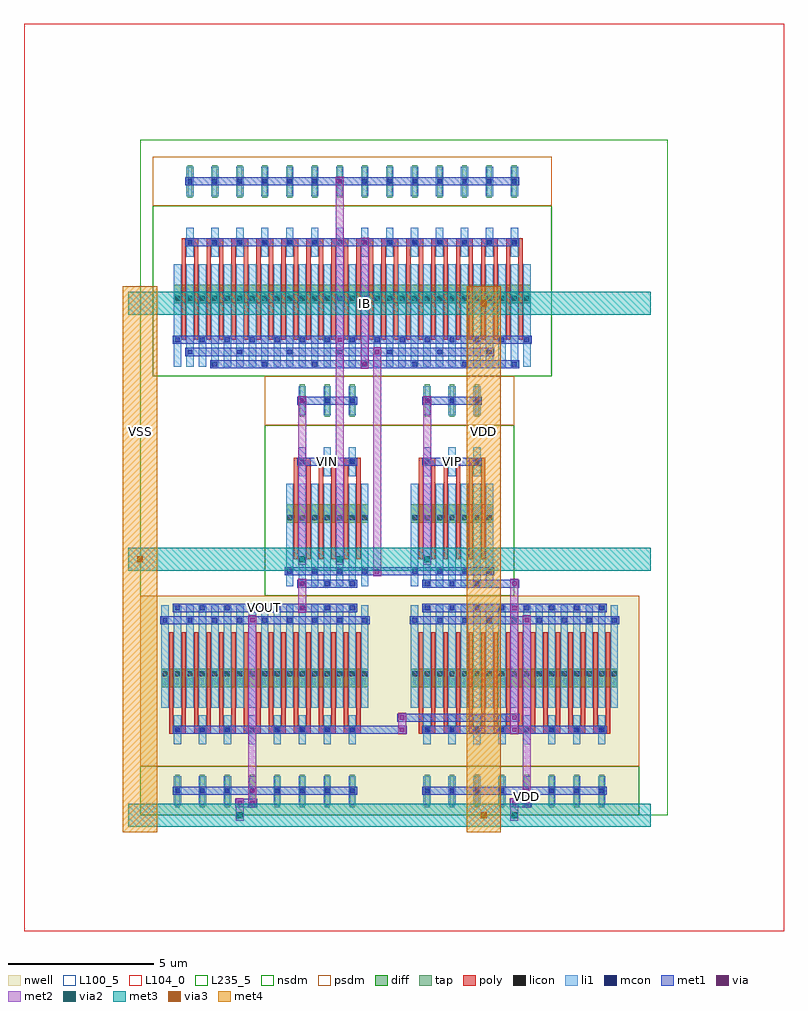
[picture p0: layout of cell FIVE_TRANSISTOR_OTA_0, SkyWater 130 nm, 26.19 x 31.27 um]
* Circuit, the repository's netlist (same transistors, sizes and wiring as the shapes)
* NGSPICE file created from FIVE_TRANSISTOR_OTA_0.ext - technology: sky130A

.subckt DCL_PMOS_S_33011438_X8_Y1_1774868971 a_200_252# w_0_0#
X0 a_200_252# a_200_252# w_0_0# w_0_0# sky130_fd_pr__pfet_01v8 ad=0.0882 pd=0.91 as=0.0882 ps=0.91 w=0.63 l=0.15 M=16
.ends

.subckt NMOS_4T_45526871_X3_Y1_1774868972 a_147_504# a_200_252# a_230_504# a_241_1232#
X0 a_230_504# a_200_252# a_147_504# a_241_1232# sky130_fd_pr__nfet_01v8 ad=0.0882 pd=0.91 as=0.16695 ps=1.79 w=0.63 l=0.15 M=6
.ends

.subckt SCM_NMOS_53863688_X7_Y1_1774868974 a_147_504# a_200_252# a_402_504#
X0 a_147_504# a_200_252# a_200_252# a_147_504# sky130_fd_pr__nfet_01v8 ad=0.0882 pd=0.91 as=0.0882 ps=0.91 w=0.63 l=0.15 M=14
X1 a_402_504# a_200_252# a_147_504# a_147_504# sky130_fd_pr__nfet_01v8 ad=0.0882 pd=0.91 as=0.0882 ps=0.91 w=0.63 l=0.15 M=14
.ends

.subckt PMOS_S_10792591_X8_Y1_1774868973 a_200_252# w_0_0# a_230_504#
X0 a_230_504# a_200_252# w_0_0# w_0_0# sky130_fd_pr__pfet_01v8 ad=0.0882 pd=0.91 as=0.0882 ps=0.91 w=0.63 l=0.15 M=16
.ends

.subckt FIVE_TRANSISTOR_OTA_0 IB VOUT VIP VIN VSS VDD
XDCL_PMOS_S_33011438_X8_Y1_1774868971_0 m1_1462_560# VDD DCL_PMOS_S_33011438_X8_Y1_1774868971
XNMOS_4T_45526871_X3_Y1_1774868972_0 m1_1548_1652# VIN VOUT VSS NMOS_4T_45526871_X3_Y1_1774868972
XSCM_NMOS_53863688_X7_Y1_1774868974_0 VSS IB m1_1548_1652# SCM_NMOS_53863688_X7_Y1_1774868974
XNMOS_4T_45526871_X3_Y1_1774868972_1 m1_1548_1652# VIP m1_1462_560# VSS NMOS_4T_45526871_X3_Y1_1774868972
XPMOS_S_10792591_X8_Y1_1774868973_0 m1_1462_560# VDD VOUT PMOS_S_10792591_X8_Y1_1774868973
.ends

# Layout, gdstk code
from math import pi, radians
import gdstk
lib = gdstk.Library(unit=1e-6, precision=1e-09)
def R(c, l, rs):  # rectangles x0, y0, x1, y1
    for r in rs: c.add(gdstk.rectangle(r[:2], r[2:], *l))
def A(c, l, x, y, w, h, nx, ny, dx, dy):  # array of equal rectangles
    R(c, l, [(x+i*dx, y+j*dy, x+i*dx+w, y+j*dy+h) for i in range(nx) for j in range(ny)])
def P(c, l, *ps):  # polygons
    for p in ps: c.add(gdstk.Polygon(p, *l))
nwell = (64, 20)
diff = (65, 20)
tap = (65, 44)
poly = (66, 20)
licon = (66, 44)
li1 = (67, 20)
mcon = (67, 44)
met1 = (68, 20)
via = (68, 44)
met2 = (69, 20)
via2 = (69, 44)
met3 = (70, 20)
via3 = (70, 44)
met4 = (71, 20)
nsdm = (93, 44)
psdm = (94, 20)
L100_5 = (100, 5)
L104_0 = (104, 0)
L235_5 = (235, 5)

scm_nmos_53863688_x7_y1_ = lib.new_cell('SCM_NMOS_53863688_X7_Y1_1774868974')
R(scm_nmos_53863688_x7_y1_, diff, [(0.735,2.52,13.025,3.15)])
A(scm_nmos_53863688_x7_y1_, tap, 1.205, 6.16, 0.17, 1.12, 14, 1, 0.86, 0)
A(scm_nmos_53863688_x7_y1_, poly, 1, 1.26, 0.15, 3.36, 28, 1, 0.43, 0)
A(scm_nmos_53863688_x7_y1_, poly, 1, 4.485, 0.58, 0.27, 14, 1, 0.86, 0)
A(scm_nmos_53863688_x7_y1_, licon, 0.775, 2.6, 0.17, 0.17, 3, 1, 0.43, 0)
A(scm_nmos_53863688_x7_y1_, licon, 1.635, 2.6, 0.17, 0.17, 3, 1, 0.43, 0)
A(scm_nmos_53863688_x7_y1_, licon, 2.495, 2.6, 0.17, 0.17, 3, 1, 0.43, 0)
A(scm_nmos_53863688_x7_y1_, licon, 3.355, 2.6, 0.17, 0.17, 3, 1, 0.43, 0)
A(scm_nmos_53863688_x7_y1_, licon, 4.215, 2.6, 0.17, 0.17, 3, 1, 0.43, 0)
A(scm_nmos_53863688_x7_y1_, licon, 5.075, 2.6, 0.17, 0.17, 3, 1, 0.43, 0)
A(scm_nmos_53863688_x7_y1_, licon, 5.935, 2.6, 0.17, 0.17, 3, 1, 0.43, 0)
A(scm_nmos_53863688_x7_y1_, licon, 6.795, 2.6, 0.17, 0.17, 3, 1, 0.43, 0)
A(scm_nmos_53863688_x7_y1_, licon, 7.655, 2.6, 0.17, 0.17, 3, 1, 0.43, 0)
A(scm_nmos_53863688_x7_y1_, licon, 8.515, 2.6, 0.17, 0.17, 3, 1, 0.43, 0)
A(scm_nmos_53863688_x7_y1_, licon, 9.375, 2.6, 0.17, 0.17, 3, 1, 0.43, 0)
A(scm_nmos_53863688_x7_y1_, licon, 10.235, 2.6, 0.17, 0.17, 3, 1, 0.43, 0)
A(scm_nmos_53863688_x7_y1_, licon, 11.095, 2.6, 0.17, 0.17, 3, 1, 0.43, 0)
A(scm_nmos_53863688_x7_y1_, licon, 11.955, 2.6, 0.17, 0.17, 3, 1, 0.43, 0)
A(scm_nmos_53863688_x7_y1_, licon, 1.205, 4.535, 0.17, 0.17, 14, 2, 0.86, 2.1)
A(scm_nmos_53863688_x7_y1_, li1, 0.735, 0.335, 0.25, 3.53, 29, 1, 0.43, 0)
A(scm_nmos_53863688_x7_y1_, li1, 1.165, 4.115, 0.25, 1.01, 14, 2, 0.86, 2.1)
A(scm_nmos_53863688_x7_y1_, mcon, 1.205, 0.335, 0.17, 0.17, 7, 1, 1.72, 0)
A(scm_nmos_53863688_x7_y1_, mcon, 2.065, 0.755, 0.17, 0.17, 7, 1, 1.72, 0)
A(scm_nmos_53863688_x7_y1_, mcon, 0.775, 1.175, 0.17, 0.17, 15, 1, 0.86, 0)
A(scm_nmos_53863688_x7_y1_, mcon, 1.205, 4.535, 0.17, 0.17, 14, 2, 0.86, 2.1)
R(scm_nmos_53863688_x7_y1_, met1, [(1.12,0.28,11.78,0.56), (1.98,0.7,12.64,0.98), (0.69,1.12,13.07,1.4), (1.12,4.48,12.64,4.76), (1.12,6.58,12.64,6.86)])
R(scm_nmos_53863688_x7_y1_, via, [(6.375,0.345,6.525,0.495), (7.235,1.185,7.385,1.335), (6.375,4.545,6.525,4.695), (7.235,6.645,7.385,6.795)])
R(scm_nmos_53863688_x7_y1_, met2, [(6.31,0.26,6.59,4.78), (7.17,1.1,7.45,6.88)])
R(scm_nmos_53863688_x7_y1_, nsdm, [(0,0,13.76,5.88)])
R(scm_nmos_53863688_x7_y1_, psdm, [(0,5.88,13.76,7.56)])
R(scm_nmos_53863688_x7_y1_, L100_5, [(0,0,13.76,7.56)])

dcl_pmos_s_33011438_x8_y = lib.new_cell('DCL_PMOS_S_33011438_X8_Y1_1774868971')
R(dcl_pmos_s_33011438_x8_y, nwell, [(0,0,8.6,7.56)])
R(dcl_pmos_s_33011438_x8_y, diff, [(0.735,2.52,7.865,3.15)])
A(dcl_pmos_s_33011438_x8_y, tap, 1.205, 6.16, 0.17, 1.12, 8, 1, 0.86, 0)
A(dcl_pmos_s_33011438_x8_y, poly, 1, 1.26, 0.15, 3.36, 16, 1, 0.43, 0)
A(dcl_pmos_s_33011438_x8_y, poly, 1, 4.485, 0.58, 0.27, 8, 1, 0.86, 0)
A(dcl_pmos_s_33011438_x8_y, licon, 0.775, 2.6, 0.17, 0.17, 3, 1, 0.43, 0)
A(dcl_pmos_s_33011438_x8_y, licon, 1.635, 2.6, 0.17, 0.17, 3, 1, 0.43, 0)
A(dcl_pmos_s_33011438_x8_y, licon, 2.495, 2.6, 0.17, 0.17, 3, 1, 0.43, 0)
A(dcl_pmos_s_33011438_x8_y, licon, 3.355, 2.6, 0.17, 0.17, 3, 1, 0.43, 0)
A(dcl_pmos_s_33011438_x8_y, licon, 4.215, 2.6, 0.17, 0.17, 3, 1, 0.43, 0)
A(dcl_pmos_s_33011438_x8_y, licon, 5.075, 2.6, 0.17, 0.17, 3, 1, 0.43, 0)
A(dcl_pmos_s_33011438_x8_y, licon, 5.935, 2.6, 0.17, 0.17, 3, 1, 0.43, 0)
A(dcl_pmos_s_33011438_x8_y, licon, 6.795, 2.6, 0.17, 0.17, 3, 1, 0.43, 0)
A(dcl_pmos_s_33011438_x8_y, licon, 1.205, 4.535, 0.17, 0.17, 8, 2, 0.86, 2.1)
A(dcl_pmos_s_33011438_x8_y, li1, 0.735, 0.335, 0.25, 3.53, 17, 1, 0.43, 0)
A(dcl_pmos_s_33011438_x8_y, li1, 1.165, 4.115, 0.25, 1.01, 8, 2, 0.86, 2.1)
A(dcl_pmos_s_33011438_x8_y, mcon, 1.205, 0.335, 0.17, 0.17, 8, 2, 0.86, 4.2)
A(dcl_pmos_s_33011438_x8_y, mcon, 0.775, 0.755, 0.17, 0.17, 9, 1, 0.86, 0)
A(dcl_pmos_s_33011438_x8_y, mcon, 1.205, 6.635, 0.17, 0.17, 8, 1, 0.86, 0)
R(dcl_pmos_s_33011438_x8_y, met1, [(1.12,0.28,7.48,0.56), (0.69,0.7,7.91,0.98), (1.12,4.48,7.48,4.76), (1.12,6.58,7.48,6.86)])
R(dcl_pmos_s_33011438_x8_y, via, [(4.225,0.345,4.375,0.495), (4.655,0.765,4.805,0.915), (4.225,4.545,4.375,4.695), (4.655,6.645,4.805,6.795)])
R(dcl_pmos_s_33011438_x8_y, met2, [(4.16,0.26,4.44,4.78), (4.59,0.68,4.87,6.88)])
R(dcl_pmos_s_33011438_x8_y, nsdm, [(0,5.88,8.6,7.56)])
R(dcl_pmos_s_33011438_x8_y, psdm, [(0,0,8.6,5.88)])
R(dcl_pmos_s_33011438_x8_y, L100_5, [(0,0,8.6,7.56)])

pmos_s_10792591_x8_y1_17 = lib.new_cell('PMOS_S_10792591_X8_Y1_1774868973')
R(pmos_s_10792591_x8_y1_17, nwell, [(0,0,8.6,7.56)])
R(pmos_s_10792591_x8_y1_17, diff, [(0.735,2.52,7.865,3.15)])
A(pmos_s_10792591_x8_y1_17, tap, 1.205, 6.16, 0.17, 1.12, 8, 1, 0.86, 0)
A(pmos_s_10792591_x8_y1_17, poly, 1, 1.26, 0.15, 3.36, 16, 1, 0.43, 0)
A(pmos_s_10792591_x8_y1_17, poly, 1, 4.485, 0.58, 0.27, 8, 1, 0.86, 0)
A(pmos_s_10792591_x8_y1_17, licon, 0.775, 2.6, 0.17, 0.17, 3, 1, 0.43, 0)
A(pmos_s_10792591_x8_y1_17, licon, 1.635, 2.6, 0.17, 0.17, 3, 1, 0.43, 0)
A(pmos_s_10792591_x8_y1_17, licon, 2.495, 2.6, 0.17, 0.17, 3, 1, 0.43, 0)
A(pmos_s_10792591_x8_y1_17, licon, 3.355, 2.6, 0.17, 0.17, 3, 1, 0.43, 0)
A(pmos_s_10792591_x8_y1_17, licon, 4.215, 2.6, 0.17, 0.17, 3, 1, 0.43, 0)
A(pmos_s_10792591_x8_y1_17, licon, 5.075, 2.6, 0.17, 0.17, 3, 1, 0.43, 0)
A(pmos_s_10792591_x8_y1_17, licon, 5.935, 2.6, 0.17, 0.17, 3, 1, 0.43, 0)
A(pmos_s_10792591_x8_y1_17, licon, 6.795, 2.6, 0.17, 0.17, 3, 1, 0.43, 0)
A(pmos_s_10792591_x8_y1_17, licon, 1.205, 4.535, 0.17, 0.17, 8, 2, 0.86, 2.1)
A(pmos_s_10792591_x8_y1_17, li1, 0.735, 0.335, 0.25, 3.53, 17, 1, 0.43, 0)
A(pmos_s_10792591_x8_y1_17, li1, 1.165, 4.115, 0.25, 1.01, 8, 2, 0.86, 2.1)
A(pmos_s_10792591_x8_y1_17, mcon, 1.205, 0.335, 0.17, 0.17, 8, 2, 0.86, 4.2)
A(pmos_s_10792591_x8_y1_17, mcon, 0.775, 0.755, 0.17, 0.17, 9, 1, 0.86, 0)
A(pmos_s_10792591_x8_y1_17, mcon, 1.205, 6.635, 0.17, 0.17, 8, 1, 0.86, 0)
R(pmos_s_10792591_x8_y1_17, met1, [(1.12,0.28,7.48,0.56), (0.69,0.7,7.91,0.98), (1.12,4.48,7.48,4.76), (1.12,6.58,7.48,6.86)])
R(pmos_s_10792591_x8_y1_17, via, [(4.655,0.765,4.805,0.915), (4.655,6.645,4.805,6.795)])
R(pmos_s_10792591_x8_y1_17, met2, [(4.59,0.68,4.87,6.88)])
R(pmos_s_10792591_x8_y1_17, nsdm, [(0,5.88,8.6,7.56)])
R(pmos_s_10792591_x8_y1_17, psdm, [(0,0,8.6,5.88)])
R(pmos_s_10792591_x8_y1_17, L100_5, [(0,0,8.6,7.56)])

nmos_4t_45526871_x3_y1_1 = lib.new_cell('NMOS_4T_45526871_X3_Y1_1774868972')
R(nmos_4t_45526871_x3_y1_1, diff, [(0.735,2.52,3.565,3.15)])
A(nmos_4t_45526871_x3_y1_1, tap, 1.205, 6.16, 0.17, 1.12, 3, 1, 0.86, 0)
A(nmos_4t_45526871_x3_y1_1, poly, 1, 1.26, 0.15, 3.36, 6, 1, 0.43, 0)
A(nmos_4t_45526871_x3_y1_1, poly, 1, 4.485, 0.58, 0.27, 3, 1, 0.86, 0)
A(nmos_4t_45526871_x3_y1_1, licon, 0.775, 2.6, 0.17, 0.17, 3, 1, 0.43, 0)
A(nmos_4t_45526871_x3_y1_1, licon, 1.635, 2.6, 0.17, 0.17, 3, 1, 0.43, 0)
A(nmos_4t_45526871_x3_y1_1, licon, 2.495, 2.6, 0.17, 0.17, 3, 1, 0.43, 0)
A(nmos_4t_45526871_x3_y1_1, licon, 1.205, 4.535, 0.17, 0.17, 3, 2, 0.86, 2.1)
A(nmos_4t_45526871_x3_y1_1, li1, 0.735, 0.335, 0.25, 3.53, 7, 1, 0.43, 0)
A(nmos_4t_45526871_x3_y1_1, li1, 1.165, 4.115, 0.25, 1.01, 3, 2, 0.86, 2.1)
A(nmos_4t_45526871_x3_y1_1, mcon, 1.205, 0.335, 0.17, 0.17, 3, 2, 0.86, 4.2)
A(nmos_4t_45526871_x3_y1_1, mcon, 0.775, 0.755, 0.17, 0.17, 4, 1, 0.86, 0)
A(nmos_4t_45526871_x3_y1_1, mcon, 1.205, 6.635, 0.17, 0.17, 3, 1, 0.86, 0)
R(nmos_4t_45526871_x3_y1_1, met1, [(1.12,0.28,3.18,0.56), (0.69,0.7,3.61,0.98), (1.12,4.48,3.18,4.76), (1.12,6.58,3.18,6.86)])
R(nmos_4t_45526871_x3_y1_1, nsdm, [(0,0,4.3,5.88)])
R(nmos_4t_45526871_x3_y1_1, psdm, [(0,5.88,4.3,7.56)])
R(nmos_4t_45526871_x3_y1_1, L100_5, [(0,0,4.3,7.56)])

five_transistor_ota_0 = lib.new_cell('FIVE_TRANSISTOR_OTA_0')
R(five_transistor_ota_0, met1, [(3.28,0.28,3.6,0.56), (3.28,0.28,3.6,0.56), (3.44,0.28,3.87,0.56), (3.71,0.28,4.03,0.56), (3.71,0.28,4.03,0.56), (12.74,0.28,13.06,0.56), (12.74,0.28,13.06,0.56), (12.74,0.28,13.06,0.56), (12.9,0.28,13.33,0.56), (13.17,0.28,13.49,0.56), (13.17,0.28,13.49,0.56), (13.17,0.28,13.49,0.56), (7.31,2.8,9.03,3.08), (8.87,2.8,9.19,3.08), (8.87,2.8,9.19,3.08), (8.87,2.8,9.19,3.08), (8.87,2.8,9.19,3.08), (8.87,3.22,9.19,3.5), (8.87,3.22,9.19,3.5), (8.87,3.22,9.19,3.5), (8.87,3.22,9.19,3.5), (9.03,3.22,12.9,3.5), (12.74,3.22,13.06,3.5), (12.74,3.22,13.06,3.5), (12.74,3.22,13.06,3.5), (12.74,3.22,13.06,3.5), (5.43,7,5.75,7.28), (5.43,7,5.75,7.28), (5.43,7.84,5.75,8.12), (5.43,7.84,5.75,8.12), (11.61,7.84,12.9,8.12), (12.74,7.84,13.06,8.12), (12.74,7.84,13.06,8.12), (7.74,8.26,9.46,8.54), (8.01,8.26,8.33,8.54), (8.01,8.26,8.33,8.54), (5.43,14.14,5.75,14.42), (5.43,14.14,5.75,14.42), (9.73,14.14,10.05,14.42), (9.73,14.14,10.05,14.42), (9.73,14.14,10.05,14.42), (8.01,15.82,8.33,16.1), (8.01,15.82,8.33,16.1)])
P(five_transistor_ota_0, met1, [(0,0),(0,0),(0,0),(0,0)],
  [(0,0),(0,0),(0,0),(0,0)],
  [(0,0),(0,0),(0,0),(0,0)],
  [(0,0),(0,0),(0,0),(0,0)],
  [(0,0),(0,0),(0,0),(0,0)],
  [(0,0),(0,0),(0,0),(0,0)],
  [(0,0),(0,0),(0,0),(0,0)],
  [(0,0),(0,0),(0,0),(0,0)],
  [(0,0),(0,0),(0,0),(0,0)],
  [(0,0),(0,0),(0,0),(0,0)],
  [(0,0),(0,0),(0,0),(0,0)],
  [(0,0),(0,0),(0,0),(0,0)],
  [(0,0),(0,0),(0,0),(0,0)],
  [(0,0),(0,0),(0,0),(0,0)])
R(five_transistor_ota_0, via, [(3.365,0.345,3.515,0.495), (3.365,0.345,3.515,0.495), (3.795,0.345,3.945,0.495), (3.795,0.345,3.945,0.495), (12.825,0.345,12.975,0.495), (12.825,0.345,12.975,0.495), (12.825,0.345,12.975,0.495), (13.255,0.345,13.405,0.495), (13.255,0.345,13.405,0.495), (13.255,0.345,13.405,0.495), (8.955,2.865,9.105,3.015), (8.955,2.865,9.105,3.015), (8.955,2.865,9.105,3.015), (8.955,2.865,9.105,3.015), (8.955,3.285,9.105,3.435), (8.955,3.285,9.105,3.435), (8.955,3.285,9.105,3.435), (8.955,3.285,9.105,3.435), (12.825,3.285,12.975,3.435), (12.825,3.285,12.975,3.435), (12.825,3.285,12.975,3.435), (12.825,3.285,12.975,3.435), (5.515,7.065,5.665,7.215), (5.515,7.065,5.665,7.215), (5.515,7.905,5.665,8.055), (5.515,7.905,5.665,8.055), (12.825,7.905,12.975,8.055), (12.825,7.905,12.975,8.055), (8.095,8.325,8.245,8.475), (8.095,8.325,8.245,8.475), (5.515,14.205,5.665,14.355), (5.515,14.205,5.665,14.355), (9.815,14.205,9.965,14.355), (9.815,14.205,9.965,14.355), (9.815,14.205,9.965,14.355), (8.095,15.885,8.245,16.035), (8.095,15.885,8.245,16.035)])
R(five_transistor_ota_0, met2, [(3.3,-0.185,3.58,0.185), (3.3,-0.185,3.58,0.185), (12.76,-0.185,13.04,0.185), (12.76,-0.185,13.04,0.185), (12.76,-0.185,13.04,0.185), (3.3,0,3.58,0.42), (12.76,0,13.04,0.42), (3.3,0.26,3.58,0.58), (3.3,0.26,3.58,0.58), (3.73,0.26,4.01,0.58), (3.73,0.26,4.01,0.58), (12.76,0.26,13.04,0.58), (12.76,0.26,13.04,0.58), (12.76,0.26,13.04,0.58), (13.19,0.26,13.47,0.58), (13.19,0.26,13.47,0.58), (13.19,0.26,13.47,0.58), (3.73,0.42,4.01,0.84), (13.19,0.42,13.47,0.84), (8.89,2.78,9.17,3.1), (8.89,2.78,9.17,3.1), (8.89,2.78,9.17,3.1), (8.89,2.78,9.17,3.1), (8.89,2.94,9.17,3.36), (8.89,3.2,9.17,3.52), (8.89,3.2,9.17,3.52), (8.89,3.2,9.17,3.52), (8.89,3.2,9.17,3.52), (12.76,3.2,13.04,3.52), (12.76,3.2,13.04,3.52), (12.76,3.2,13.04,3.52), (12.76,3.2,13.04,3.52), (5.45,6.98,5.73,7.3), (5.45,6.98,5.73,7.3), (5.45,7.14,5.73,7.98), (12.76,7.14,13.04,7.98), (5.45,7.82,5.73,8.14), (5.45,7.82,5.73,8.14), (12.76,7.82,13.04,8.14), (12.76,7.82,13.04,8.14), (8.03,8.24,8.31,8.56), (8.03,8.24,8.31,8.56), (8.03,8.4,8.31,15.96), (5.45,8.635,5.73,9.005), (5.45,8.635,5.73,9.005), (6.74,8.635,7.02,9.005), (6.74,8.635,7.02,9.005), (6.74,8.635,7.02,9.005), (6.74,8.635,7.02,9.005), (9.75,8.635,10.03,9.005), (9.75,8.635,10.03,9.005), (9.75,8.635,10.03,9.005), (5.45,8.82,5.73,14.28), (6.74,8.82,7.02,16.38), (9.75,8.82,10.03,14.28), (5.45,14.12,5.73,14.44), (5.45,14.12,5.73,14.44), (9.75,14.12,10.03,14.44), (9.75,14.12,10.03,14.44), (9.75,14.12,10.03,14.44), (8.03,15.8,8.31,16.12), (8.03,15.8,8.31,16.12)])
P(five_transistor_ota_0, met2, [(0,0),(0,0),(0,0),(0,0)],
  [(0,0),(0,0),(0,0),(0,0)],
  [(0,0),(0,0),(0,0),(0,0)],
  [(0,0),(0,0),(0,0),(0,0)],
  [(0,0),(0,0),(0,0),(0,0)],
  [(0,0),(0,0),(0,0),(0,0)])
R(five_transistor_ota_0, via2, [(3.34,-0.1,3.54,0.1), (3.34,-0.1,3.54,0.1), (12.8,-0.1,13,0.1), (12.8,-0.1,13,0.1), (12.8,-0.1,13,0.1), (5.49,8.72,5.69,8.92), (5.49,8.72,5.69,8.92), (6.78,8.72,6.98,8.92), (6.78,8.72,6.98,8.92), (6.78,8.72,6.98,8.92), (6.78,8.72,6.98,8.92), (9.79,8.72,9.99,8.92), (9.79,8.72,9.99,8.92), (9.79,8.72,9.99,8.92)])
A(five_transistor_ota_0, met3, -0.4, -0.4, 4.24, 0.8, 3, 3, 3.44, 8.82)
A(five_transistor_ota_0, met3, 9.92, -0.4, 2.32, 0.8, 1, 3, 0, 8.82)
A(five_transistor_ota_0, met3, 11.44, -0.4, 2.72, 0.8, 1, 3, 0, 8.82)
A(five_transistor_ota_0, met3, 13.36, -0.4, 4.24, 0.8, 1, 3, 0, 8.82)
R(five_transistor_ota_0, met3, [(3.275,-0.4,3.605,0.4), (3.275,-0.4,3.605,0.4), (11.675,-0.4,12.005,0.4), (12.735,-0.4,13.065,0.4), (12.735,-0.4,13.065,0.4), (12.735,-0.4,13.065,0.4), (-0.165,8.42,0.165,9.22), (5.425,8.42,5.755,9.22), (5.425,8.42,5.755,9.22), (6.715,8.42,7.045,9.22), (6.715,8.42,7.045,9.22), (6.715,8.42,7.045,9.22), (6.715,8.42,7.045,9.22), (9.725,8.42,10.055,9.22), (9.725,8.42,10.055,9.22), (9.725,8.42,10.055,9.22), (11.675,17.24,12.005,18.04)])
R(five_transistor_ota_0, via3, [(11.74,-0.1,11.94,0.1), (-0.1,8.72,0.1,8.92), (11.74,17.54,11.94,17.74)])
R(five_transistor_ota_0, met4, [(-0.59,-0.59,0.59,9.41), (11.25,-0.59,12.43,9.41), (11.25,-0.165,12.43,0.165), (-0.59,8.23,0.59,18.23), (11.25,8.23,12.43,18.23), (-0.59,8.655,0.59,8.985), (11.25,17.475,12.43,17.805)])
R(five_transistor_ota_0, L104_0, [(-4,-4,22.19,27.27)])
R(five_transistor_ota_0, L235_5, [(0,0,18.19,23.27)])
five_transistor_ota_0.add(gdstk.Reference(scm_nmos_53863688_x7_y1_, (14.19,15.12), rotation=pi, x_reflection=True))
five_transistor_ota_0.add(gdstk.Reference(dcl_pmos_s_33011438_x8_y, (8.6,7.56), x_reflection=True))
five_transistor_ota_0.add(gdstk.Reference(pmos_s_10792591_x8_y1_17, (8.6,7.56), rotation=pi))
five_transistor_ota_0.add(gdstk.Reference(nmos_4t_45526871_x3_y1_1, (12.9,7.56), rotation=pi, x_reflection=True))
five_transistor_ota_0.add(gdstk.Reference(nmos_4t_45526871_x3_y1_1, (4.3,7.56)))
five_transistor_ota_0.add(gdstk.Label('IB', (7.74,17.64), layer=69, texttype=5))
five_transistor_ota_0.add(gdstk.Label('VOUT', (4.3,7.14), layer=68, texttype=5))
five_transistor_ota_0.add(gdstk.Label('VIP', (10.75,12.18), layer=68, texttype=5))
five_transistor_ota_0.add(gdstk.Label('VIN', (6.45,12.18), layer=68, texttype=5))
five_transistor_ota_0.add(gdstk.Label('VSS', (6.88,12.6), layer=69, texttype=5))
five_transistor_ota_0.add(gdstk.Label('VSS', (0,13.23), layer=71, texttype=5))
five_transistor_ota_0.add(gdstk.Label('VSS', (0,13.23), layer=71, texttype=5))
five_transistor_ota_0.add(gdstk.Label('VSS', (0,13.23), layer=71, texttype=5))
five_transistor_ota_0.add(gdstk.Label('VSS', (0,13.23), layer=71, texttype=5))
five_transistor_ota_0.add(gdstk.Label('VSS', (0,13.23), layer=71, texttype=5))
five_transistor_ota_0.add(gdstk.Label('VSS', (0,13.23), layer=71, texttype=5))
five_transistor_ota_0.add(gdstk.Label('VSS', (0,13.23), layer=71, texttype=5))
five_transistor_ota_0.add(gdstk.Label('VSS', (0,13.23), layer=71, texttype=5))
five_transistor_ota_0.add(gdstk.Label('VDD', (13.33,0.63), layer=69, texttype=5))
five_transistor_ota_0.add(gdstk.Label('VDD', (11.84,13.23), layer=71, texttype=5))
five_transistor_ota_0.add(gdstk.Label('VDD', (11.84,13.23), layer=71, texttype=5))
five_transistor_ota_0.add(gdstk.Label('VDD', (11.84,13.23), layer=71, texttype=5))
five_transistor_ota_0.add(gdstk.Label('VDD', (11.84,13.23), layer=71, texttype=5))
five_transistor_ota_0.add(gdstk.Label('VDD', (11.84,13.23), layer=71, texttype=5))
five_transistor_ota_0.add(gdstk.Label('VDD', (11.84,13.23), layer=71, texttype=5))
five_transistor_ota_0.add(gdstk.Label('VDD', (11.84,13.23), layer=71, texttype=5))
five_transistor_ota_0.add(gdstk.Label('VDD', (11.84,13.23), layer=71, texttype=5))

lib.write_gds('FIVE_TRANSISTOR_OTA_0.gds')
